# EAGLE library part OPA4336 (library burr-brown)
Single-Supply, MicroPower CMOS Operational Amplifiers MicroAmplifier (TM) Series

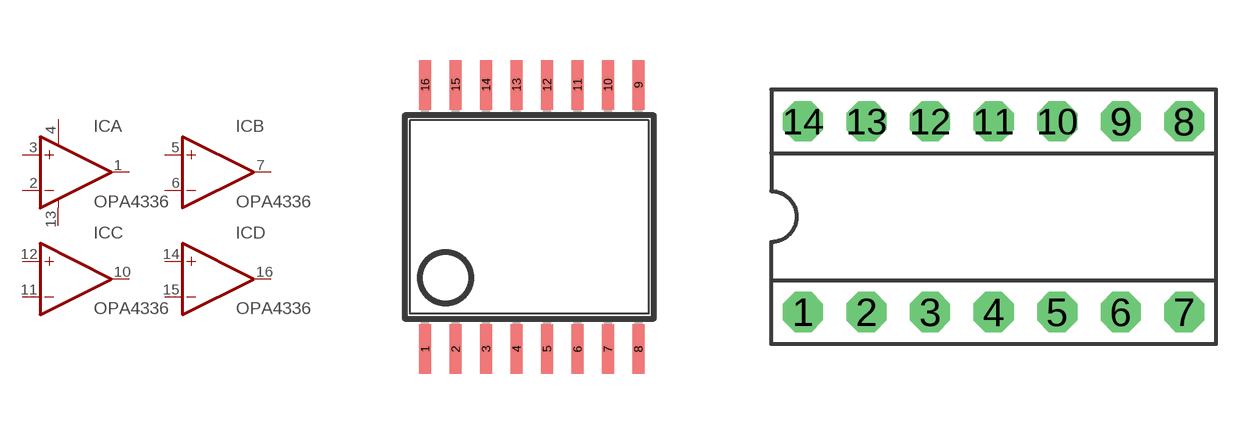
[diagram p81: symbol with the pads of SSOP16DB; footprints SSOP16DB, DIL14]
Designator prefix IC; gates A=OP-AMP+- B=OP-AMP C=OP-AMP D=OP-AMP

## OPA4336E  [SSOP16DB]
1  A:OUT  out
2  A:-IN  in
3  A:+IN  in
4  A:V+  pwr
5  B:+IN  in
6  B:-IN  in
7  B:OUT  out
10  C:OUT  out
11  C:-IN  in
12  C:+IN  in
13  A:V-  pwr
14  D:+IN  in
15  D:-IN  in
16  D:OUT  out

## OPA4336P  [DIL14]
1  A:OUT  out
2  A:-IN  in
3  A:+IN  in
4  A:V+  pwr
5  B:+IN  in
6  B:-IN  in
7  B:OUT  out
8  C:OUT  out
9  C:-IN  in
10  C:+IN  in
11  A:V-  pwr
12  D:+IN  in
13  D:-IN  in
14  D:OUT  out

## OPA4336U  [SO14]
Pads as for DIL14

## Footprint SSOP16DB (pad centres in mm)
Small Shrink Outline Package
smd 0.305 x 1.245: 1 -2.667,-3.302; 2 -1.905,-3.302; 3 -1.143,-3.302; 4 -0.381,-3.302; 5 0.381,-3.302; 6 1.143,-3.302; 7 1.905,-3.302; 8 2.667,-3.302; 9 2.667,3.302; 10 1.905,3.302; 11 1.143,3.302; 12 0.381,3.302; 13 -0.381,3.302; 14 -1.143,3.302; 15 -1.905,3.302; 16 -2.667,3.302

## Footprint DIL14 (pad centres in mm)
Dual In Line
drill 0.813 pad 1.6 octagon: 1 -7.62,-3.81; 2 -5.08,-3.81; 3 -2.54,-3.81; 4 0,-3.81; 5 2.54,-3.81; 6 5.08,-3.81; 7 7.62,-3.81; 8 7.62,3.81; 9 5.08,3.81; 10 2.54,3.81; 11 0,3.81; 12 -2.54,3.81; 13 -5.08,3.81; 14 -7.62,3.81

## Footprint SO14 (pad centres in mm)
Small Outline Package
smd 0.61 x 2.21: 1 -3.81,-2.603; 2 -2.54,-2.603; 3 -1.27,-2.603; 4 0,-2.603; 5 1.27,-2.603; 6 2.54,-2.603; 7 3.81,-2.603; 8 3.81,2.603; 9 2.54,2.603; 10 1.27,2.603; 11 0,2.603; 12 -1.27,2.603; 13 -2.54,2.603; 14 -3.81,2.603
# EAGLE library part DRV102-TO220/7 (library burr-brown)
Burr Brown - Solenoid / Valve Driver Device: DRV102 Package: TO220/7 NB: Tab connected to Pin 4 (Gnd)

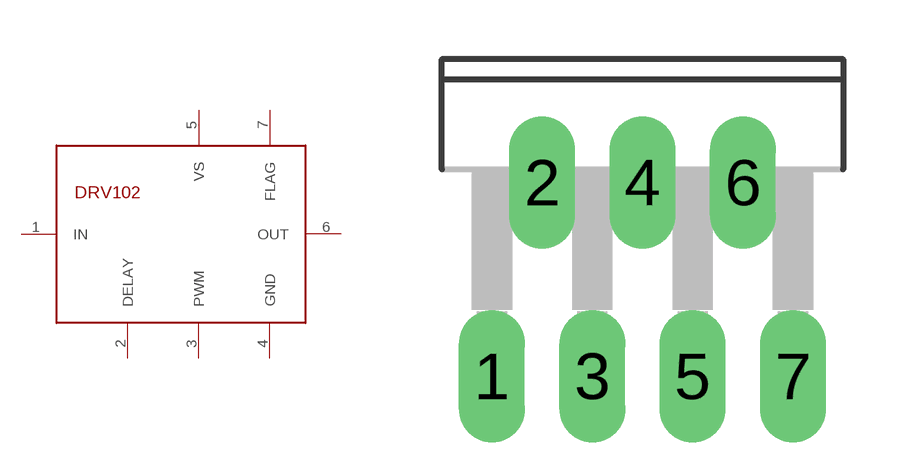
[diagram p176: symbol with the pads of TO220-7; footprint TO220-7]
Designator prefix IC

## DRV102-TO220/7  [TO220-7]
1  IN  in
2  DELAY
3  PWM
4  GND  sup
5  VS  pwr
6  OUT  out
7  FLAG  out

## Footprint TO220-7 (pad centres in mm)
Molded Package
drill 1.118 pad 1.626 long: 1 -3.81,-8.036; 2 -2.54,-3.126; 3 -1.27,-8.036; 4 0,-3.126; 5 1.27,-8.036; 6 2.54,-3.126; 7 3.81,-8.036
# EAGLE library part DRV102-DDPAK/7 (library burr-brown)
Burr Brown - Solenoid / Valve Driver Device: DRV102 Package: 7 Lead DDPAK NB: Tab connected to Pin 4 (Gnd)

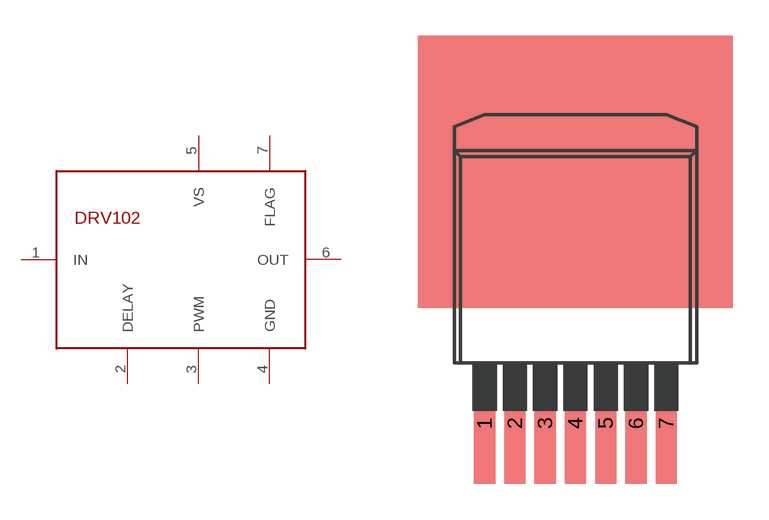
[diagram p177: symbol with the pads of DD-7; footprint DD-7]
Designator prefix IC

## DRV102-DDPAK/7  [DD-7]
1  IN  in
2  DELAY
3  PWM
4  GND  sup
5  VS  pwr
6  OUT  out
7  FLAG  out

## Footprint DD-7 (pad centres in mm)
DPAC
smd 0.889 x 5.08: 1 -3.81,-6.985; 2 -2.54,-6.985; 3 -1.27,-6.985; 4 0,-6.985; 5 1.27,-6.985; 6 2.54,-6.985; 7 3.81,-6.985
